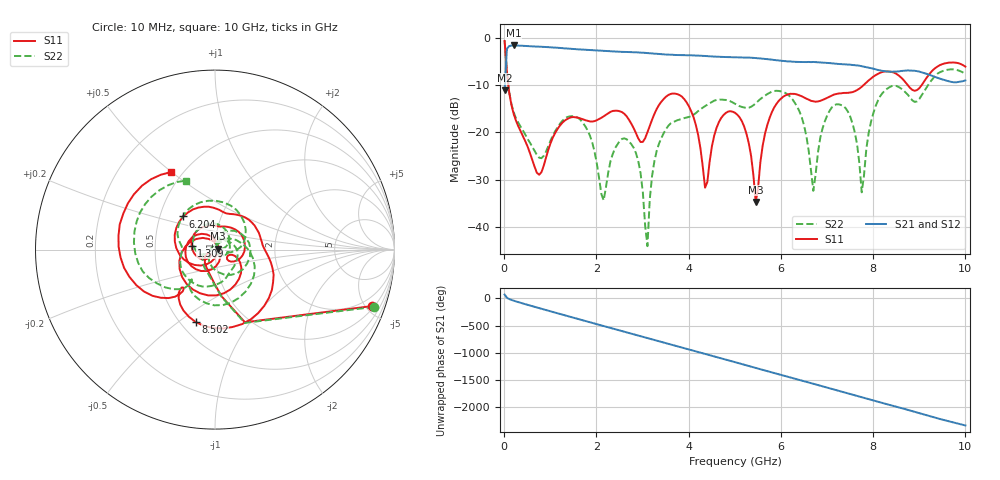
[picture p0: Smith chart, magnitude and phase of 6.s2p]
!Agilent Technologies,N5230C,MY49000813,A.09.42.22
!Agilent N5230C: A.09.42.22
!Date: Friday, August 21, 2026 19:37:37
!Correction: S11(Full 2 Port(1,2))
!S21(Full 2 Port(1,2))
!S12(Full 2 Port(1,2))
!S22(Full 2 Port(1,2))
!S2P File: Measurements: S11, S21, S12, S22:
# Hz S  dB  R 50
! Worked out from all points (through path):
!   201 points, 10 MHz to 10 GHz, reference 50 ohm
!   highest |S21| = -1.58 dB at 209.8 MHz (marker M1); lowest = -11.1 dB at 10 MHz (marker M2)
!   lowest |S11| = -34.8 dB at 5.455 GHz (marker M3), VSWR 1.04, Z = 51.8 + j0.62 ohm
!   |S11| at or under -10 dB: 92.05 MHz to 7.791 GHz (7.699 GHz wide, 195 % of centre); 8.751 GHz to 9.052 GHz (300.9 MHz wide, 3.38 % of centre)
!   |S22| runs from -44.1 to -0.5 dB; largest |S21 - S12| = 0.0038
!   S11 on the Smith chart (normalised r, x): 10 MHz: 1.16, -5.52; 1.309 GHz: 0.77, +0.04; 6.204 GHz: 0.66, +0.26; 8.502 GHz: 0.59, -0.58; 10 GHz: 0.43, +0.50
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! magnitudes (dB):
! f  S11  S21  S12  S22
! 10 MHz  -0.6  -11.1  -11.2  -0.5
! 209.8 MHz  -16.2  -1.6  -1.6  -15.8
! 759.2 MHz  -29.0  -1.9  -1.9  -25.4
! 1.309 GHz  -17.5  -2.2  -2.2  -17.1
! 1.708 GHz  -17.2  -2.5  -2.5  -18.0
! 2.158 GHz  -16.6  -2.7  -2.7  -34.4
! 2.807 GHz  -19.1  -3.0  -3.0  -23.2
! 3.107 GHz  -20.0  -3.2  -3.2  -44.1
! 3.357 GHz  -14.2  -3.4  -3.4  -22.4
! 4.006 GHz  -14.5  -3.6  -3.7  -16.7
! 4.356 GHz  -31.7  -3.8  -3.8  -14.4
! 5.005 GHz  -15.8  -4.1  -4.1  -13.9
! 5.455 GHz  -34.8  -4.3  -4.3  -13.8
! 5.704 GHz  -18.5  -4.5  -4.5  -11.9
! 6.204 GHz  -11.8  -5.0  -5.0  -12.5
! 6.703 GHz  -13.4  -5.1  -5.1  -32.4
! 7.253 GHz  -11.8  -5.5  -5.5  -14.0
! 7.752 GHz  -10.3  -6.0  -6.0  -32.7
! 7.952 GHz  -8.6  -6.4  -6.4  -17.8
! 8.352 GHz  -7.1  -7.2  -7.1  -10.4
! 8.502 GHz  -7.6  -7.1  -7.1  -10.2
! 10 GHz  -6.1  -9.0  -9.0  -7.6
